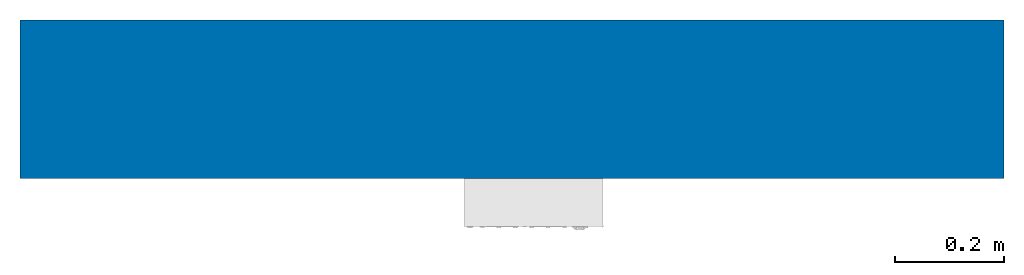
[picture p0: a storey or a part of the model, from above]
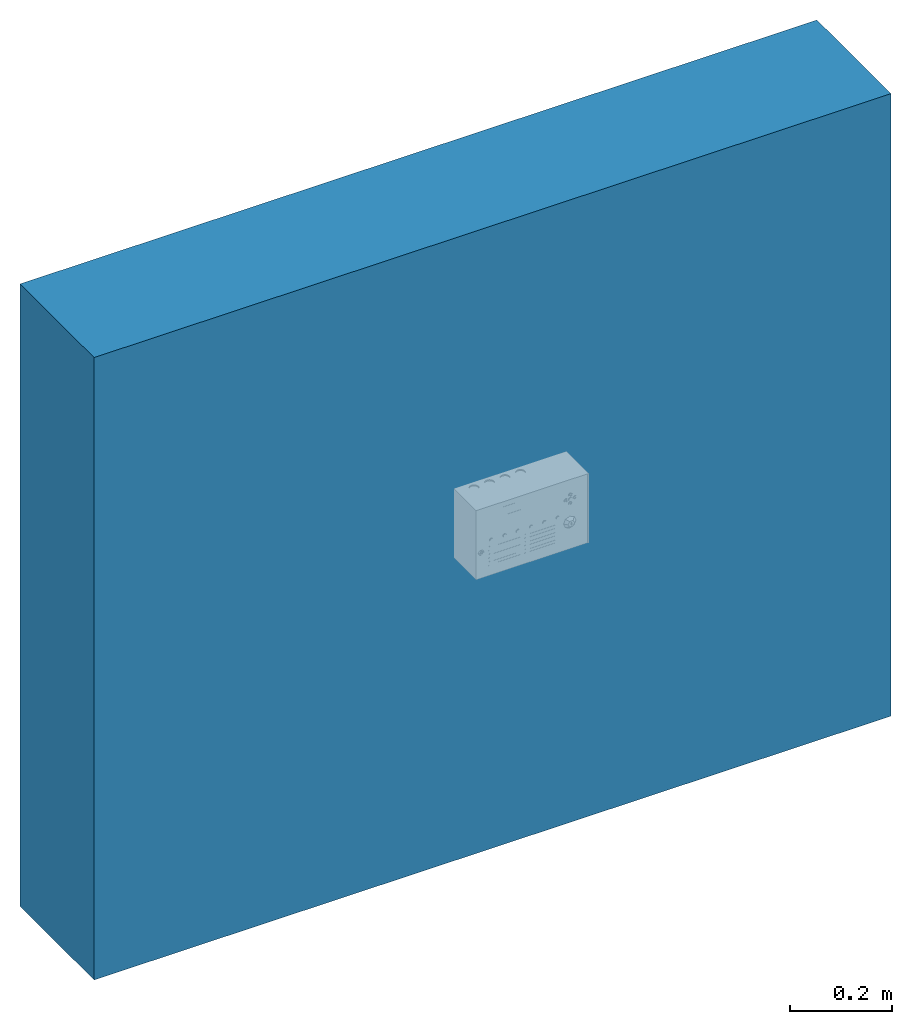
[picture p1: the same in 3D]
Properties of the parts of a building model (IFC2X3)

# File
Description: ViewDefinition [CoordinationView]
File name: Project Number
Time: 2014-10-31T09:33:39
Written by: The EXPRESS Data Manager Version 5.01.0100.02.64mod : 6 Jun 2012
Made in: 20140709_2115(x64) - Exporter 2014.0.2014.0709 - Default UI
Comment: STEP Physical File produced by: The EXPRESS Data Manager Version 5.01.0100.02.64mod : 6 Jun 2012 * Module: EDMstepFileFactory/EDMstandAlone * Creation date: Fri Oct 31 09:33:39 2014 * Host: BIM-HP * Database: C:\Users\dcole\AppData\Local\Temp\{12E34BAD-E901-4D80-B91A-310218FEAB3F}\ifc * Database version: 5507 * Database creation date: Fri Oct 31 09:33:38 2014 * Schema: IFC2X3 * Model: DataRepository.ifc * Model creation date: Fri Oct 31 09:33:39 2014 * Header model: DataRepository.ifc_HeaderModel * Header model creation date: Fri Oct 31 09:33:39 2014 * EDMuser: sdai-user * EDMgroup: sdai-group * License ID and type: 5605 : Permanent license. Expiry date: * EDMstepFileFactory options: 020000

# IfcProject, Project Number
LongName: Project Name; Phase: Project Status

# IfcSite, Default
RefLatitude: 51, 30, 0, 549316; RefLongitude: 0, -7, -34, -450321; RefElevation: 0 mm

# IfcBuilding
Pset_BuildingCommon - NumberOfStoreys: 1
Other - Project Address: Enter address here; Project Name: Project Name; Project Issue Date: Issue Date; Project Status: Project Status; Project Number: Project Number; Client Name: Owner

# IfcBuildingStorey, Level 0
LongName: Level 0; Elevation: 0 mm
Graphics - Line Pattern: Centre; Symbol: Level Head - Circle: Level Head - Circle; Symbol at End 2 Default: no; Color: 0; Symbol at End 1 Default: yes; Line Weight: 1
Constraints - Elevation Base: Project Base Point; Elevation: 0 mm
Identity Data - Structural: no; Building Story: yes; Name: Level 0
Dimensions - Computation Height: 0 mm

# IfcBuildingElementProxy: IDR-6A, IDR-6A:IDR-6A:225286
In: Level 0
Material: Platinum, Polypropylene, Default, UHMW, Black, UHMW, White
Phasing - Phase Created: New Construction
Constraints - Offset: 1842.06 mm; Moves With Nearby Elements: no; Level: Level: Level 0; Host: Level : Level 0
Pset_ManufacturerTypeInformation - Manufacturer: Notifier by Honeywell
Pset_BuildingElementProxyCommon - Reference: IDR-6A
Identity Data - Assembly Description: Misc. Other Fire Protection Systems; Model: 002-452; URL: www.notifierfiresystems.co.uk; Assembly Code: D4090900; Type Comments: IDR-6A Active Repeater; Manufacturer: Notifier by Honeywell; Description: Repeater Panel
Title Text - Fax No.: +44 (0) 1273 376894; Address line 1: Caburn House, 2B Brooks Road, Lewes BN7 2BY; Tel No.: +44 (0) 1444 230300; Email: sales@notifierfiresystems.co.uk

# IfcWallStandardCase: Basic Wall:Cav - 102 75i 100 p - Lwt, Basic Wall:Cav - 102 75i 100 p - Lwt:216702
In: Level 0
Type - PredefinedType: STANDARD; Material: Brick, Common 102.5 mm, Fiberglass Batt 75 mm, Concrete Masonry Units 100 mm, Gypsum Wall Board 12.5 mm
Type - Identity Data - Keynote: F10
Type - Materials and Finishes - Structural Material: Concrete Masonry Units
Type - Analytical Properties - Absorptance: 0.7; Thermal mass: 298413; Roughness: 3; Heat Transfer Coefficient (U): 0.23622; Thermal Resistance (R): 4.23334
Type - Construction - Function: Exterior; Width: 290 mm; Wrapping at Inserts: Both
Type - Graphics - Coarse Scale Fill Pattern: Solid fill; Coarse Scale Fill Color: 16514043
Constraints - Related to Mass: no; Base Constraint: Level: Level 0; Base Offset: 1117.44 mm; Base is Attached: no; Location Line: Wall Centerline; Unconnected Height: 1486.32 mm; Top is Attached: no; Base Extension Distance: 0 mm; Room Bounding: yes; Top Offset: 0 mm; Top Extension Distance: 0 mm
Structural - Enable Analytical Model: no; Structural Usage: Non-bearing; Structural: no
Phasing - Phase Created: New Construction
Dimensions - Area: 2.67537 m2; Length: 1800 mm; Volume: 0.775859 m3
Pset_WallCommon - Reference: Cav - 102 75i 100 p - Lwt; LoadBearing: no; ExtendToStructure: no; IsExternal: yes; ThermalTransmittance: 0.23622 kg/K/s3
